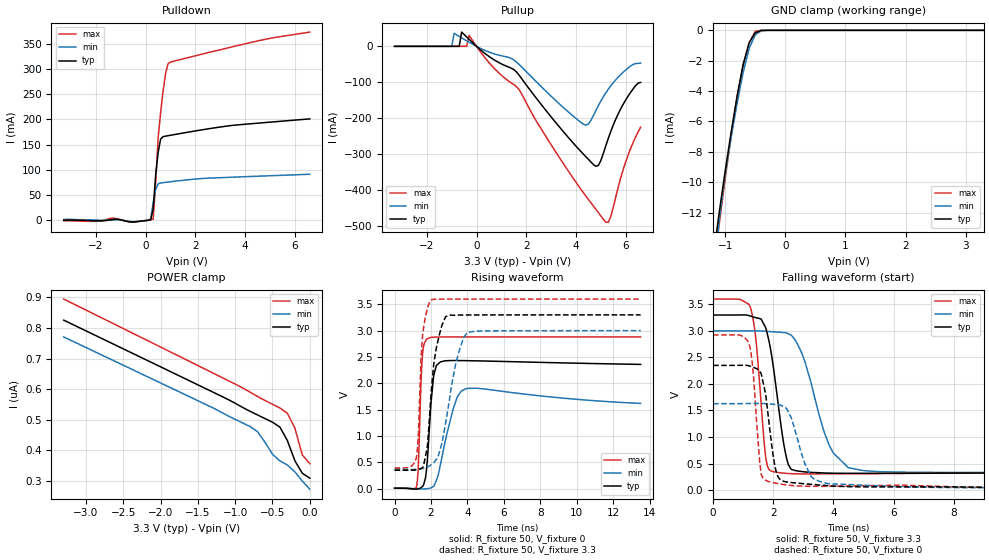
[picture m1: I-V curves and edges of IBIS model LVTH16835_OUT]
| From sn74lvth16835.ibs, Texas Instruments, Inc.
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|************* LVTH16835 OUTPUT (3.3 V) MODEL**************
[Model]   LVTH16835_OUT
Model_type  Output
Polarity   Non-Inverting
Enable   Active-Low
Vmeas = 1.5V
Cref = 50pF
Rref = 500
Vref = 0
| variable   typ   min   max
C_comp   11p   NA   NA
[Temperature Range]   50   100   0
[Voltage range]   3.3   3   3.6
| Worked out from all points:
|   slope of the pulldown table from 0 to 0.495 V, typ, clamps not added: 3.73 ohm
|   slope of the pullup table from 0 to 0.495 V, typ, clamps not added: 17.8 ohm
|   GND clamp passes 1 mA (typ) near -0.61 V on its own axis
|   rising waveform, R_fixture 50, V_fixture 0: 20-80 % time 289ps typ, 616ps min, 169ps max; typ from 0.006 V to 2.36 V
|   falling waveform, R_fixture 50, V_fixture 3.3: 20-80 % time 440ps typ, 819ps min, 283ps max; typ from 3.3 V to 0.325 V
|   rising waveform, R_fixture 50, V_fixture 3.3: 20-80 % time 485ps typ, 822ps min, 246ps max; typ from 0.347 V to 3.3 V
|   falling waveform, R_fixture 50, V_fixture 0: 20-80 % time 324ps typ, 547ps min, 230ps max; typ from 2.35 V to 0.027 V
|Process range|   weak   strong
[Pullup]
|   50C:3.3V:   100C:3V:weak   0C:3.6V:strong
|   Voltage   I(typ)   I(min)   I(max)
-3.3V     70.97uA    42.59uA    121.4uA
-700mV    57.28uA    27.84mA    109.7uA
-600mV    39.72mA    23.68mA    108.8uA
-400mV    26.25mA    15.53mA    64.69uA
-300mV    19.6mA     11.54mA    30.71mA
1.6V      -70.77mA   -43.37mA   -111.6mA
4.3V      -299.8mA   -216.6mA   -407.2mA
4.8V      -333.6mA   -178.4mA   -453mA
5.2V      -276.4mA   -129.2mA   -488.9mA
5.4V      -236.5mA   -109.7mA   -473mA
5.9V      -160.8mA   -71.81mA   -342.3mA
6.6V      -100.4mA   -46.63mA   -224.8mA
[Pulldown]
|   50C:3.3V:   100C:3V:weak   0C:3.6V:strong
|   Voltage   I(typ)   I(min)   I(max)
-3.3V     332.5uA    1.888mA    -240.9uA
-1.3V     2.202mA    1.028mA    4.704mA
100mV     446.7uA    438.3uA    436.3uA
200mV     1.158mA    2.926mA    1.112mA
300mV     23.17mA    35.42mA    2.898mA
400mV     90.36mA    61.52mA    74.52mA
500mV     134.9mA    72.51mA    164mA
600mV     161.2mA    74.23mA    213.6mA
800mV     166.9mA    75.5mA     291.2mA
900mV     167.8mA    76.1mA     310.4mA
4.3V      191.7mA    87.22mA    353mA
6.6V      201mA      91.47mA    372.8mA
[GND Clamp]
|   50C:3.3V:   100C:3V:weak   0C:3.6V:strong
|   Voltage   I(typ)   I(min)   I(max)
-3.3V     -685.2mA   -608.2mA   -762.6mA
-1.2V     -15.03mA   -17.11mA   -15.97mA
-1.1V     -12.06mA   -12.54mA   -12.83mA
-1V       -9.304mA   -9.548mA   -9.805mA
-900mV    -6.723mA   -7.064mA   -6.957mA
-800mV    -4.321mA   -4.798mA   -4.38mA
-700mV    -2.239mA   -2.774mA   -2.338mA
-600mV    -824.9uA   -1.184mA   -826.4uA
-500mV    -166uA     -304.8uA   -67.24uA
-400mV    -8.07uA    -32.36uA   -1.279uA
-300mV    -297.6nA   -1.728uA   -82.12nA
3.3V      309.7nA    352.6nA    332nA
[POWER Clamp]
|   50C:3.3V:   100C:3V:weak   0C:3.6V:strong
|   Voltage   I(typ)   I(min)   I(max)
-3.3V     825.2nA    770.4nA    893.9nA
-1.4V     602.3nA    550.7nA    664.9nA
-1.1V     566.9nA    513.5nA    628.7nA
-800mV    527.7nA    478.2nA    590.1nA
-700mV    515.8nA    461.1nA    576nA
-600mV    504nA      426.9nA    562.9nA
-500mV    492.2nA    387.6nA    550.8nA
-400mV    476.3nA    365.9nA    538.6nA
-300mV    432.1nA    352.6nA    520.9nA
-200mV    366.7nA    330.4nA    473.3nA
-100mV    325.7nA    299.9nA    385.4nA
0V        309.7nA    273.8nA    357nA
[ramp]
| variable   typ   min   max
dV/dt_r   1.4669E+00/3.0091E-10  1.1508E+00/7.5881E-10  1.7359E+00/1.6221E-10
dV/dt_f   1.7929E+00/4.4146E-10  1.6020E+00/8.2165E-10  1.9784E+00/2.8517E-10
[Rising Waveform]
R_fixture = 50
V_fixture = 0
V_fixture_min = 0
V_fixture_max = 0
C_fixture = 0
L_fixture = 0
|   50C:3.3V:   100C:3V:weak   0C:3.6V:strong
|   Time   V(typ)   V(min)   V(max)
0s        5.808mV    4.198mV    7.992mV
1.2ns     -11.01mV   -5.318mV   15.03mV
1.3ns     -4.219mV   -7.557mV   374.9mV
1.5ns     28.7mV     -8.54mV    2.376V
1.75ns    343.5mV    -3.855mV   2.837V
2.15ns    2.149V     41.74mV    2.877V
2.5ns     2.401V     426.5mV    2.879V
3.25ns    2.432V     1.547V     2.881V
3.9ns     2.43V      1.895V     2.88V
13.5ns    2.358V     1.618V     2.881V
[Falling Waveform]
R_fixture = 50
V_fixture = 3.3
V_fixture_min = 3
V_fixture_max = 3.6
C_fixture = 0
L_fixture = 0
|   50C:3.3V:   100C:3V:weak   0C:3.6V:strong
|   Time   V(typ)   V(min)   V(max)
0s        3.3V       3V         3.6V
1.25ns    3.279V     3.001V     3.435V
1.45ns    3.247V     3.001V     2.698V
1.75ns    3.06V      2.994V     619.7mV
1.95ns    2.527V     2.986V     354.8mV
2.35ns    868mV      2.97V      318.1mV
2.6ns     389.8mV    2.92V      308.7mV
3.85ns    319.1mV    861.4mV    304.9mV
4.5ns     314.2mV    420.3mV    307.3mV
13.5ns    325.4mV    342.6mV    334mV
[Rising Waveform]
R_fixture = 50
V_fixture = 3.3
V_fixture_min = 3
V_fixture_max = 3.6
C_fixture = 0
L_fixture = 0
|   50C:3.3V:   100C:3V:weak   0C:3.6V:strong
|   Time   V(typ)   V(min)   V(max)
0s        347.4mV    361.5mV    391.1mV
1.2ns     355.6mV    364.7mV    582.7mV
1.55ns    399.5mV    380.7mV    2.953V
1.8ns     793.2mV    407.6mV    3.416V
2ns       1.784V     447.4mV    3.583V
2.3ns     2.682V     556.8mV    3.595V
2.8ns     3.263V     1.239V     3.598V
3.35ns    3.293V     2.361V     3.599V
4ns       3.297V     2.968V     3.6V
13.5ns    3.3V       2.999V     3.6V
[Falling Waveform]
R_fixture = 50
V_fixture = 0
V_fixture_min = 0
V_fixture_max = 0
C_fixture = 0
L_fixture = 0
|   50C:3.3V:   100C:3V:weak   0C:3.6V:strong
|   Time   V(typ)   V(min)   V(max)
0s        2.35V      1.628V     2.925V
1.2ns     2.342V     1.631V     2.76V
1.35ns    2.313V     1.632V     2.116V
1.6ns     2.196V     1.632V     300.8mV
1.85ns    1.319V     1.624V     157.1mV
2.2ns     215.5mV    1.606V     116.7mV
2.6ns     140.9mV    1.363V     86.14mV
3.25ns    108mV      265.3mV    69.28mV
3.75ns    85.23mV    129.6mV    69.96mV
13.5ns    27.07mV    29.69mV    15.95mV
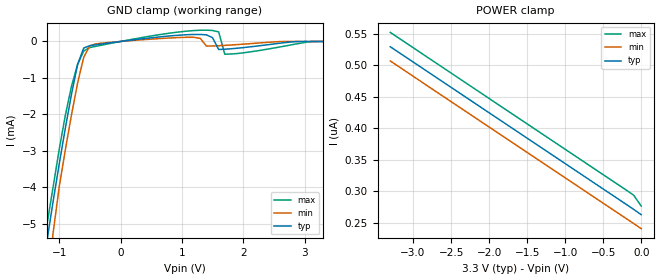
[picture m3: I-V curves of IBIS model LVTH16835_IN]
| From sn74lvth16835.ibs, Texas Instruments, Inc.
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|   LVTH16835 Input (IN) model
[Model]   LVTH16835_IN
Model_type  Input
Polarity   Non-Inverting
Vinl = 0.8V
Vinh = 2.0V
| variable   typ   min   max
C_comp   4.5p   NA   NA
[Temperature Range]   50   100   0
[Voltage range]   3.3   3   3.6
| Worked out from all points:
|   GND clamp passes 1 mA (typ) near -0.74 V on its own axis
|Process range|   weak   strong
[GND Clamp]
|   50C:3.3V:   100C:3V:weak   0C:3.6V:strong
|   Voltage   I(typ)   I(min)   I(max)
-3.3V     -75.35mA   -79.87mA   -70.96mA
-1.2V     -5.479mA   -7.102mA   -5.037mA
-1.1V     -4.404mA   -5.27mA    -4.006mA
-800mV    -1.458mA   -2.022mA   -1.236mA
-700mV    -631.6uA   -1.144mA   -631uA
-600mV    -178.7uA   -434uA     -262.3uA
-400mV    -91.05uA   -64.15uA   -131.7uA
1.3V      192.8uA    85.28uA    308.6uA
1.5V      105.2uA    -123.6uA   301.8uA
1.6V      -219.6uA   -116.4uA   262.8uA
1.7V      -212.5uA   -107.1uA   -348.5uA
3.3V      262.6nA    264.7nA    229.4nA
[POWER Clamp]
|   50C:3.3V:   100C:3V:weak   0C:3.6V:strong
|   Voltage   I(typ)   I(min)   I(max)
-3.3V     529.2nA    506.6nA    551.9nA
-200mV    279.2nA    256.6nA    301.9nA
-100mV    271.1nA    248.5nA    293.6nA
0V        262.6nA    240.4nA    276.3nA
